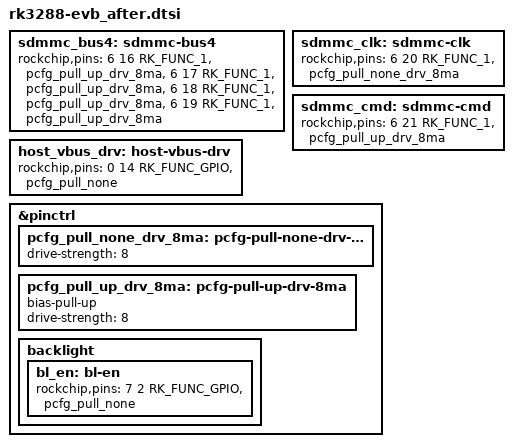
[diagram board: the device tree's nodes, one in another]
};

&pinctrl {
	pcfg_pull_none_drv_8ma: pcfg-pull-none-drv-8ma {
		drive-strength = <8>;
	};

	pcfg_pull_up_drv_8ma: pcfg-pull-up-drv-8ma {
		bias-pull-up;
		drive-strength = <8>;
	};

	backlight {
		bl_en: bl-en {
			rockchip,pins = <7 2 RK_FUNC_GPIO &pcfg_pull_none>;
		};
		};
	};

	sdmmc {
		/*
		 * Default drive strength isn't enough to achieve even
		 * high-speed mode on EVB board so bump up to 8ma.
		 */
		sdmmc_bus4: sdmmc-bus4 {
			rockchip,pins = <6 16 RK_FUNC_1 &pcfg_pull_up_drv_8ma>,
					<6 17 RK_FUNC_1 &pcfg_pull_up_drv_8ma>,
					<6 18 RK_FUNC_1 &pcfg_pull_up_drv_8ma>,
					<6 19 RK_FUNC_1 &pcfg_pull_up_drv_8ma>;
		};

		sdmmc_clk: sdmmc-clk {
			rockchip,pins = <6 20 RK_FUNC_1 &pcfg_pull_none_drv_8ma>;
		};

		sdmmc_cmd: sdmmc-cmd {
			rockchip,pins = <6 21 RK_FUNC_1 &pcfg_pull_up_drv_8ma>;
		};
	};

	usb {
		host_vbus_drv: host-vbus-drv {
			rockchip,pins = <0 14 RK_FUNC_GPIO &pcfg_pull_none>;
		};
